VERSION 5.7 ;
  NOWIREEXTENSIONATPIN ON ;
  DIVIDERCHAR "/" ;
  BUSBITCHARS "[]" ;
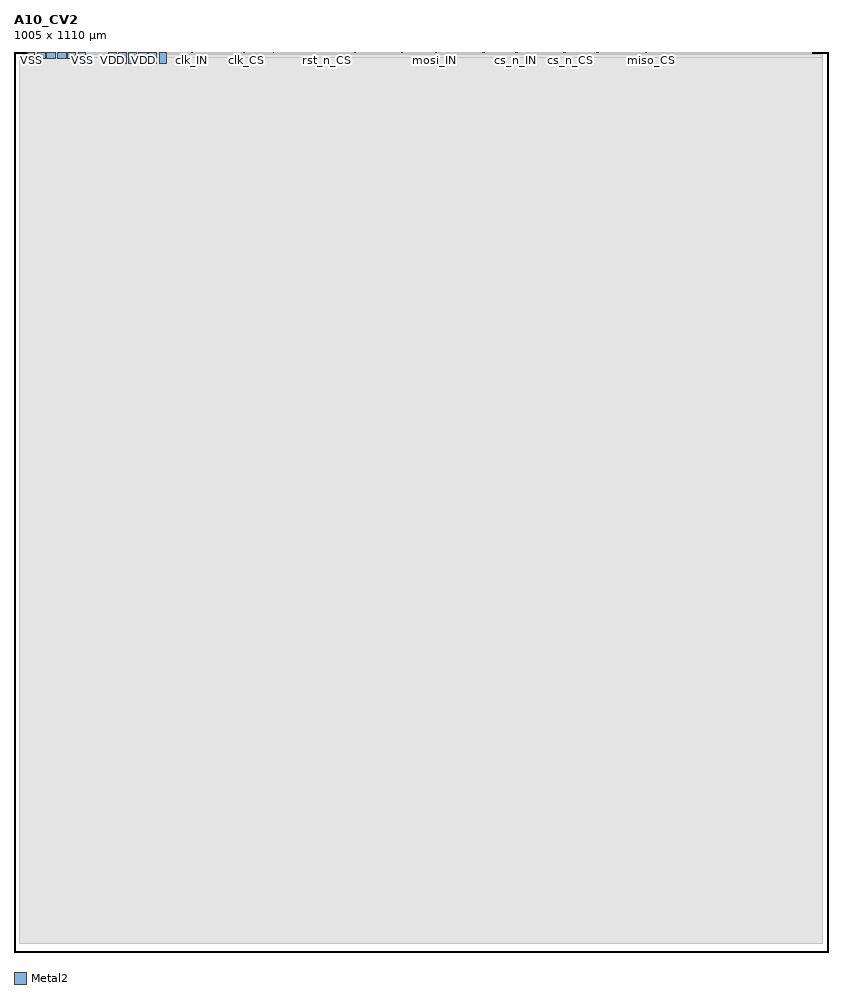
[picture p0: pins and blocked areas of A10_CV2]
MACRO A10_CV2
  CLASS BLOCK ;
  FOREIGN A10_CV2 ;
  ORIGIN 0.000 0.000 ;
  SIZE 1005.000 BY 1110.000 ;
  PIN VDD
    DIRECTION INOUT ;
    USE POWER ;
    PORT
      LAYER Metal2 ;
        RECT 116.360 1095.400 125.860 1110.000 ;
    END
  END VDD
  PIN VDD
    DIRECTION INOUT ;
    USE POWER ;
    PORT
      LAYER Metal2 ;
        RECT 128.760 1095.400 139.010 1110.000 ;
    END
  END VDD
  PIN VDD
    DIRECTION INOUT ;
    USE POWER ;
    PORT
      LAYER Metal2 ;
        RECT 140.610 1095.400 150.860 1110.000 ;
    END
  END VDD
  PIN VDD
    DIRECTION INOUT ;
    USE POWER ;
    PORT
      LAYER Metal2 ;
        RECT 154.140 1095.400 164.390 1110.000 ;
    END
  END VDD
  PIN VDD
    DIRECTION INOUT ;
    USE POWER ;
    PORT
      LAYER Metal2 ;
        RECT 165.990 1095.400 176.240 1110.000 ;
    END
  END VDD
  PIN VDD
    DIRECTION INOUT ;
    USE POWER ;
    PORT
      LAYER Metal2 ;
        RECT 179.140 1095.400 188.640 1110.000 ;
    END
  END VDD
  PIN VSS
    DIRECTION INOUT ;
    USE GROUND ;
    PORT
      LAYER Metal2 ;
        RECT 16.360 1102.400 25.860 1110.000 ;
    END
  END VSS
  PIN VSS
    DIRECTION INOUT ;
    USE GROUND ;
    PORT
      LAYER Metal2 ;
        RECT 28.760 1102.400 39.010 1110.000 ;
    END
  END VSS
  PIN VSS
    DIRECTION INOUT ;
    USE GROUND ;
    PORT
      LAYER Metal2 ;
        RECT 40.610 1102.400 50.860 1110.000 ;
    END
  END VSS
  PIN VSS
    DIRECTION INOUT ;
    USE GROUND ;
    PORT
      LAYER Metal2 ;
        RECT 54.140 1102.400 64.390 1110.000 ;
    END
  END VSS
  PIN VSS
    DIRECTION INOUT ;
    USE GROUND ;
    PORT
      LAYER Metal2 ;
        RECT 65.990 1102.400 76.240 1110.000 ;
    END
  END VSS
  PIN VSS
    DIRECTION INOUT ;
    USE GROUND ;
    PORT
      LAYER Metal2 ;
        RECT 79.140 1102.400 88.640 1110.000 ;
    END
  END VSS
  PIN clk_CS
    DIRECTION OUTPUT ;
    USE SIGNAL ;
    ANTENNADIFFAREA 0.360800 ;
    PORT
      LAYER Metal2 ;
        RECT 286.260 1109.000 286.640 1110.000 ;
    END
  END clk_CS
  PIN clk_IE
    DIRECTION OUTPUT ;
    USE SIGNAL ;
    ANTENNADIFFAREA 0.536800 ;
    PORT
      LAYER Metal2 ;
        RECT 278.235 1109.000 278.615 1110.000 ;
    END
  END clk_IE
  PIN clk_IN
    DIRECTION INPUT ;
    USE SIGNAL ;
    ANTENNAGATEAREA 1.183000 ;
    ANTENNADIFFAREA 0.410400 ;
    PORT
      LAYER Metal2 ;
        RECT 218.760 1109.000 219.140 1110.000 ;
    END
  END clk_IN
  PIN clk_OE
    DIRECTION OUTPUT ;
    USE SIGNAL ;
    ANTENNADIFFAREA 0.360800 ;
    PORT
      LAYER Metal2 ;
        RECT 219.490 1109.000 219.870 1110.000 ;
    END
  END clk_OE
  PIN clk_OUT
    DIRECTION OUTPUT ;
    USE SIGNAL ;
    ANTENNADIFFAREA 0.360800 ;
    PORT
      LAYER Metal2 ;
        RECT 220.220 1109.000 220.600 1110.000 ;
    END
  END clk_OUT
  PIN clk_PD
    DIRECTION OUTPUT ;
    USE SIGNAL ;
    ANTENNADIFFAREA 0.360800 ;
    PORT
      LAYER Metal2 ;
        RECT 279.290 1109.000 279.670 1110.000 ;
    END
  END clk_PD
  PIN clk_PU
    DIRECTION OUTPUT ;
    USE SIGNAL ;
    ANTENNADIFFAREA 0.360800 ;
    PORT
      LAYER Metal2 ;
        RECT 283.655 1109.000 284.035 1110.000 ;
    END
  END clk_PU
  PIN clk_SL
    DIRECTION OUTPUT ;
    USE SIGNAL ;
    ANTENNADIFFAREA 0.360800 ;
    PORT
      LAYER Metal2 ;
        RECT 220.950 1109.000 221.330 1110.000 ;
    END
  END clk_SL
  PIN cs_n_CS
    DIRECTION OUTPUT ;
    USE SIGNAL ;
    ANTENNADIFFAREA 0.360800 ;
    PORT
      LAYER Metal2 ;
        RECT 686.260 1109.000 686.640 1110.000 ;
    END
  END cs_n_CS
  PIN cs_n_IE
    DIRECTION OUTPUT ;
    USE SIGNAL ;
    ANTENNADIFFAREA 0.536800 ;
    PORT
      LAYER Metal2 ;
        RECT 678.235 1109.000 678.615 1110.000 ;
    END
  END cs_n_IE
  PIN cs_n_IN
    DIRECTION INPUT ;
    USE SIGNAL ;
    ANTENNAGATEAREA 0.741000 ;
    ANTENNADIFFAREA 0.410400 ;
    PORT
      LAYER Metal2 ;
        RECT 618.760 1109.000 619.140 1110.000 ;
    END
  END cs_n_IN
  PIN cs_n_OE
    DIRECTION OUTPUT ;
    USE SIGNAL ;
    ANTENNADIFFAREA 0.360800 ;
    PORT
      LAYER Metal2 ;
        RECT 619.490 1109.000 619.870 1110.000 ;
    END
  END cs_n_OE
  PIN cs_n_OUT
    DIRECTION OUTPUT ;
    USE SIGNAL ;
    ANTENNADIFFAREA 0.360800 ;
    PORT
      LAYER Metal2 ;
        RECT 620.220 1109.000 620.600 1110.000 ;
    END
  END cs_n_OUT
  PIN cs_n_PD
    DIRECTION OUTPUT ;
    USE SIGNAL ;
    ANTENNADIFFAREA 0.360800 ;
    PORT
      LAYER Metal2 ;
        RECT 679.290 1109.000 679.670 1110.000 ;
    END
  END cs_n_PD
  PIN cs_n_PU
    DIRECTION OUTPUT ;
    USE SIGNAL ;
    ANTENNADIFFAREA 0.360800 ;
    PORT
      LAYER Metal2 ;
        RECT 683.655 1109.000 684.035 1110.000 ;
    END
  END cs_n_PU
  PIN cs_n_SL
    DIRECTION OUTPUT ;
    USE SIGNAL ;
    ANTENNADIFFAREA 0.360800 ;
    PORT
      LAYER Metal2 ;
        RECT 620.950 1109.000 621.330 1110.000 ;
    END
  END cs_n_SL
  PIN miso_CS
    DIRECTION OUTPUT ;
    USE SIGNAL ;
    ANTENNADIFFAREA 0.360800 ;
    PORT
      LAYER Metal2 ;
        RECT 786.260 1109.000 786.640 1110.000 ;
    END
  END miso_CS
  PIN miso_IE
    DIRECTION OUTPUT ;
    USE SIGNAL ;
    ANTENNADIFFAREA 0.360800 ;
    PORT
      LAYER Metal2 ;
        RECT 778.235 1109.000 778.615 1110.000 ;
    END
  END miso_IE
  PIN miso_IN
    DIRECTION INPUT ;
    USE SIGNAL ;
    PORT
      LAYER Metal2 ;
        RECT 718.760 1109.000 719.140 1110.000 ;
    END
  END miso_IN
  PIN miso_OE
    DIRECTION OUTPUT ;
    USE SIGNAL ;
    ANTENNADIFFAREA 0.536800 ;
    PORT
      LAYER Metal2 ;
        RECT 719.490 1109.000 719.870 1110.000 ;
    END
  END miso_OE
  PIN miso_OUT
    DIRECTION OUTPUT ;
    USE SIGNAL ;
    ANTENNADIFFAREA 0.897600 ;
    PORT
      LAYER Metal2 ;
        RECT 720.220 1109.000 720.600 1110.000 ;
    END
  END miso_OUT
  PIN miso_PD
    DIRECTION OUTPUT ;
    USE SIGNAL ;
    ANTENNADIFFAREA 0.360800 ;
    PORT
      LAYER Metal2 ;
        RECT 779.290 1109.000 779.670 1110.000 ;
    END
  END miso_PD
  PIN miso_PU
    DIRECTION OUTPUT ;
    USE SIGNAL ;
    ANTENNADIFFAREA 0.360800 ;
    PORT
      LAYER Metal2 ;
        RECT 783.655 1109.000 784.035 1110.000 ;
    END
  END miso_PU
  PIN miso_SL
    DIRECTION OUTPUT ;
    USE SIGNAL ;
    ANTENNADIFFAREA 0.360800 ;
    PORT
      LAYER Metal2 ;
        RECT 720.950 1109.000 721.330 1110.000 ;
    END
  END miso_SL
  PIN mosi_CS
    DIRECTION OUTPUT ;
    USE SIGNAL ;
    ANTENNADIFFAREA 0.360800 ;
    PORT
      LAYER Metal2 ;
        RECT 586.260 1109.000 586.640 1110.000 ;
    END
  END mosi_CS
  PIN mosi_IE
    DIRECTION OUTPUT ;
    USE SIGNAL ;
    ANTENNADIFFAREA 0.536800 ;
    PORT
      LAYER Metal2 ;
        RECT 578.235 1109.000 578.615 1110.000 ;
    END
  END mosi_IE
  PIN mosi_IN
    DIRECTION INPUT ;
    USE SIGNAL ;
    ANTENNAGATEAREA 0.741000 ;
    ANTENNADIFFAREA 0.410400 ;
    PORT
      LAYER Metal2 ;
        RECT 518.760 1109.000 519.140 1110.000 ;
    END
  END mosi_IN
  PIN mosi_OE
    DIRECTION OUTPUT ;
    USE SIGNAL ;
    ANTENNADIFFAREA 0.360800 ;
    PORT
      LAYER Metal2 ;
        RECT 519.490 1109.000 519.870 1110.000 ;
    END
  END mosi_OE
  PIN mosi_OUT
    DIRECTION OUTPUT ;
    USE SIGNAL ;
    ANTENNADIFFAREA 0.360800 ;
    PORT
      LAYER Metal2 ;
        RECT 520.220 1109.000 520.600 1110.000 ;
    END
  END mosi_OUT
  PIN mosi_PD
    DIRECTION OUTPUT ;
    USE SIGNAL ;
    ANTENNADIFFAREA 0.360800 ;
    PORT
      LAYER Metal2 ;
        RECT 579.290 1109.000 579.670 1110.000 ;
    END
  END mosi_PD
  PIN mosi_PU
    DIRECTION OUTPUT ;
    USE SIGNAL ;
    ANTENNADIFFAREA 0.360800 ;
    PORT
      LAYER Metal2 ;
        RECT 583.655 1109.000 584.035 1110.000 ;
    END
  END mosi_PU
  PIN mosi_SL
    DIRECTION OUTPUT ;
    USE SIGNAL ;
    ANTENNADIFFAREA 0.360800 ;
    PORT
      LAYER Metal2 ;
        RECT 520.950 1109.000 521.330 1110.000 ;
    END
  END mosi_SL
  PIN rst_n_CS
    DIRECTION OUTPUT ;
    USE SIGNAL ;
    ANTENNADIFFAREA 0.360800 ;
    PORT
      LAYER Metal2 ;
        RECT 386.260 1109.000 386.640 1110.000 ;
    END
  END rst_n_CS
  PIN rst_n_IE
    DIRECTION OUTPUT ;
    USE SIGNAL ;
    ANTENNADIFFAREA 0.536800 ;
    PORT
      LAYER Metal2 ;
        RECT 378.235 1109.000 378.615 1110.000 ;
    END
  END rst_n_IE
  PIN rst_n_IN
    DIRECTION INPUT ;
    USE SIGNAL ;
    ANTENNAGATEAREA 0.498500 ;
    ANTENNADIFFAREA 0.410400 ;
    PORT
      LAYER Metal2 ;
        RECT 318.760 1109.000 319.140 1110.000 ;
    END
  END rst_n_IN
  PIN rst_n_OE
    DIRECTION OUTPUT ;
    USE SIGNAL ;
    ANTENNADIFFAREA 0.360800 ;
    PORT
      LAYER Metal2 ;
        RECT 319.490 1109.000 319.870 1110.000 ;
    END
  END rst_n_OE
  PIN rst_n_OUT
    DIRECTION OUTPUT ;
    USE SIGNAL ;
    ANTENNADIFFAREA 0.360800 ;
    PORT
      LAYER Metal2 ;
        RECT 320.220 1109.000 320.600 1110.000 ;
    END
  END rst_n_OUT
  PIN rst_n_PD
    DIRECTION OUTPUT ;
    USE SIGNAL ;
    ANTENNADIFFAREA 0.360800 ;
    PORT
      LAYER Metal2 ;
        RECT 379.290 1109.000 379.670 1110.000 ;
    END
  END rst_n_PD
  PIN rst_n_PU
    DIRECTION OUTPUT ;
    USE SIGNAL ;
    ANTENNADIFFAREA 0.360800 ;
    PORT
      LAYER Metal2 ;
        RECT 383.655 1109.000 384.035 1110.000 ;
    END
  END rst_n_PU
  PIN rst_n_SL
    DIRECTION OUTPUT ;
    USE SIGNAL ;
    ANTENNADIFFAREA 0.360800 ;
    PORT
      LAYER Metal2 ;
        RECT 320.950 1109.000 321.330 1110.000 ;
    END
  END rst_n_SL
  PIN sclk_CS
    DIRECTION OUTPUT ;
    USE SIGNAL ;
    ANTENNADIFFAREA 0.360800 ;
    PORT
      LAYER Metal2 ;
        RECT 486.260 1109.000 486.640 1110.000 ;
    END
  END sclk_CS
  PIN sclk_IE
    DIRECTION OUTPUT ;
    USE SIGNAL ;
    ANTENNADIFFAREA 0.536800 ;
    PORT
      LAYER Metal2 ;
        RECT 478.235 1109.000 478.615 1110.000 ;
    END
  END sclk_IE
  PIN sclk_IN
    DIRECTION INPUT ;
    USE SIGNAL ;
    ANTENNAGATEAREA 1.183000 ;
    ANTENNADIFFAREA 0.410400 ;
    PORT
      LAYER Metal2 ;
        RECT 418.760 1109.000 419.140 1110.000 ;
    END
  END sclk_IN
  PIN sclk_OE
    DIRECTION OUTPUT ;
    USE SIGNAL ;
    ANTENNADIFFAREA 0.360800 ;
    PORT
      LAYER Metal2 ;
        RECT 419.490 1109.000 419.870 1110.000 ;
    END
  END sclk_OE
  PIN sclk_OUT
    DIRECTION OUTPUT ;
    USE SIGNAL ;
    ANTENNADIFFAREA 0.360800 ;
    PORT
      LAYER Metal2 ;
        RECT 420.220 1109.000 420.600 1110.000 ;
    END
  END sclk_OUT
  PIN sclk_PD
    DIRECTION OUTPUT ;
    USE SIGNAL ;
    ANTENNADIFFAREA 0.360800 ;
    PORT
      LAYER Metal2 ;
        RECT 479.290 1109.000 479.670 1110.000 ;
    END
  END sclk_PD
  PIN sclk_PU
    DIRECTION OUTPUT ;
    USE SIGNAL ;
    ANTENNADIFFAREA 0.360800 ;
    PORT
      LAYER Metal2 ;
        RECT 483.655 1109.000 484.035 1110.000 ;
    END
  END sclk_PU
  PIN sclk_SL
    DIRECTION OUTPUT ;
    USE SIGNAL ;
    ANTENNADIFFAREA 0.360800 ;
    PORT
      LAYER Metal2 ;
        RECT 420.950 1109.000 421.330 1110.000 ;
    END
  END sclk_SL
  OBS
      LAYER Nwell ;
        RECT 19.730 23.090 984.910 1090.190 ;
      LAYER Metal1 ;
        RECT 20.160 23.220 984.480 1090.060 ;
      LAYER Metal2 ;
        RECT 26.160 1102.100 28.460 1109.220 ;
        RECT 39.310 1102.100 40.310 1109.220 ;
        RECT 51.160 1102.100 53.840 1109.220 ;
        RECT 64.690 1102.100 65.690 1109.220 ;
        RECT 76.540 1102.100 78.840 1109.220 ;
        RECT 88.940 1102.100 116.060 1109.220 ;
        RECT 16.360 1095.100 116.060 1102.100 ;
        RECT 126.160 1095.100 128.460 1109.220 ;
        RECT 139.310 1095.100 140.310 1109.220 ;
        RECT 151.160 1095.100 153.840 1109.220 ;
        RECT 164.690 1095.100 165.690 1109.220 ;
        RECT 176.540 1095.100 178.840 1109.220 ;
        RECT 188.940 1108.700 218.460 1109.220 ;
        RECT 221.630 1108.700 277.935 1109.220 ;
        RECT 278.915 1108.700 278.990 1109.220 ;
        RECT 279.970 1108.700 283.355 1109.220 ;
        RECT 284.335 1108.700 285.960 1109.220 ;
        RECT 286.940 1108.700 318.460 1109.220 ;
        RECT 321.630 1108.700 377.935 1109.220 ;
        RECT 378.915 1108.700 378.990 1109.220 ;
        RECT 379.970 1108.700 383.355 1109.220 ;
        RECT 384.335 1108.700 385.960 1109.220 ;
        RECT 386.940 1108.700 418.460 1109.220 ;
        RECT 421.630 1108.700 477.935 1109.220 ;
        RECT 478.915 1108.700 478.990 1109.220 ;
        RECT 479.970 1108.700 483.355 1109.220 ;
        RECT 484.335 1108.700 485.960 1109.220 ;
        RECT 486.940 1108.700 518.460 1109.220 ;
        RECT 521.630 1108.700 577.935 1109.220 ;
        RECT 578.915 1108.700 578.990 1109.220 ;
        RECT 579.970 1108.700 583.355 1109.220 ;
        RECT 584.335 1108.700 585.960 1109.220 ;
        RECT 586.940 1108.700 618.460 1109.220 ;
        RECT 621.630 1108.700 677.935 1109.220 ;
        RECT 678.915 1108.700 678.990 1109.220 ;
        RECT 679.970 1108.700 683.355 1109.220 ;
        RECT 684.335 1108.700 685.960 1109.220 ;
        RECT 686.940 1108.700 718.460 1109.220 ;
        RECT 721.630 1108.700 777.935 1109.220 ;
        RECT 778.915 1108.700 778.990 1109.220 ;
        RECT 779.970 1108.700 783.355 1109.220 ;
        RECT 784.335 1108.700 785.960 1109.220 ;
        RECT 786.940 1108.700 983.220 1109.220 ;
        RECT 188.940 1095.100 983.220 1108.700 ;
        RECT 16.360 23.330 983.220 1095.100 ;
      LAYER Metal3 ;
        RECT 16.360 23.380 983.270 1108.660 ;
      LAYER Metal4 ;
        RECT 7.160 10.520 997.480 1106.470 ;
      LAYER Metal5 ;
        RECT 7.160 10.520 997.480 1102.760 ;
  END
END A10_CV2
END LIBRARY

